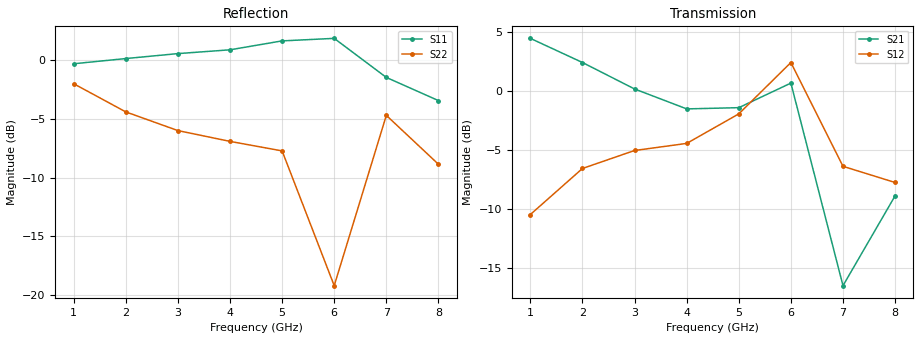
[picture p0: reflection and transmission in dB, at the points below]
! HXTR4103 Common Collector
! Vce=18V  Ic=130mA
# ghz s ma r 50
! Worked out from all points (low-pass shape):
!   8 points, 1 GHz to 8 GHz, reference 50 ohm
!   highest |S21| = 4.45 dB at 1 GHz (marker M1); lowest = -16.5 dB at 7 GHz (marker M2)
!   |S21| within 3 dB of the highest: start of sweep to 2.427 GHz
!   lowest |S11| = -3.5 dB at 8 GHz (marker M3), VSWR 5.06, Z = 16.6 + j39.9 ohm
!   |S11| at or under -10 dB: nowhere
!   |S22| runs from -19.2 to -2.0 dB; largest |S21 - S12| = 1.6
1  0.96 -79.0  1.67 -56.0  0.3 24.0  0.79 130.0
2  1.01 -144.0  1.32 -104.0  0.47 -24.0  0.6 95.0
3  1.06 164.0  1.02 -146.0  0.56 -69.0  0.5 77.0
4  1.1 120.0  0.84 177.0  0.6 -111.0  0.45 68.0
5  1.2 74.0  0.85 142.0  0.8 -148.0  0.41 45.0
6  1.23 -37.0  1.08 68.0  1.32 136.0  0.11 164.0
7  0.84 157.0  0.15 -8.0  0.48 58.0  0.58 76.0
8  0.67 99.0  0.36 78.0  0.41 68.0  0.36 64.0
